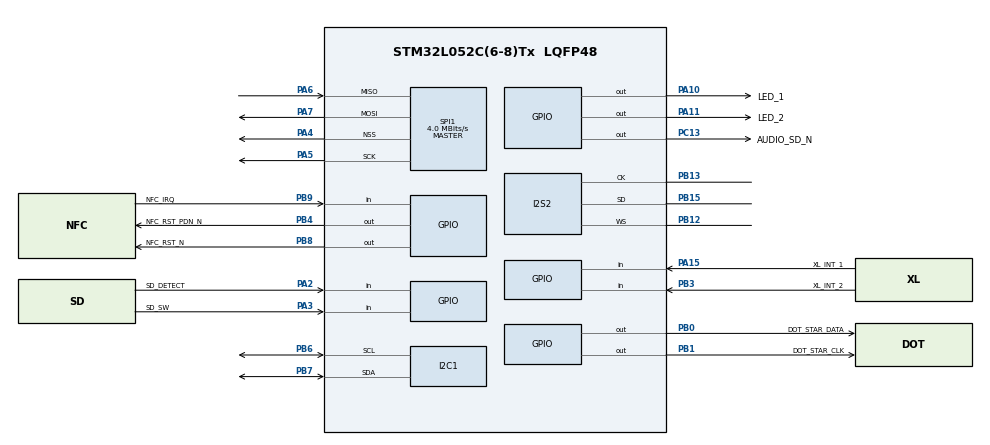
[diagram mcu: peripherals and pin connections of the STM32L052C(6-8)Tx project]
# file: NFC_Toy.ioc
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Dma.Request0=SPI2_TX
Dma.SPI2_TX.0.Direction=DMA_MEMORY_TO_PERIPH
Dma.SPI2_TX.0.Instance=DMA1_Channel5
Dma.SPI2_TX.0.MemDataAlignment=DMA_MDATAALIGN_HALFWORD
Dma.SPI2_TX.0.MemInc=DMA_MINC_ENABLE
Dma.SPI2_TX.0.Mode=DMA_NORMAL
Dma.SPI2_TX.0.PeriphDataAlignment=DMA_PDATAALIGN_HALFWORD
Dma.SPI2_TX.0.PeriphInc=DMA_PINC_DISABLE
Dma.SPI2_TX.0.Priority=DMA_PRIORITY_LOW
FATFS._FS_MINIMIZE=1
I2C1.Timing=0x00303D5B
I2S2.AudioFreq=I2S_AUDIOFREQ_44K
I2S2.ErrorAudioFreq=3.3 %
I2S2.Instance=SPI$Index
I2S2.RealAudioFreq=45.454 KHz
I2S2.VirtualMode=I2S_MODE_MASTER
Mcu.Family=STM32L0
Mcu.Name=STM32L052C(6-8)Tx
Mcu.Package=LQFP48
NVIC.DMA1_Channel4_5_6_7_IRQn=true\:0\:0\:false\:false\:true\:false
PA10.GPIO_Label=LED_1
PA10.Signal=GPIO_Output
PA11.GPIO_Label=LED_2
PA11.Signal=GPIO_Output
PA13.Mode=Serial_Wire
PA13.Signal=SYS_SWDIO
PA14.Mode=Serial_Wire
PA14.Signal=SYS_SWCLK
PA15.GPIO_Label=XL_INT_1
PA15.Signal=GPIO_Input
PA2.GPIO_Label=SD_DETECT
PA2.Signal=GPIO_Input
PA3.GPIO_Label=SD_SW
PA3.Signal=GPIO_Input
PA4.Mode=NSS_Signal_Hard_Output
PA4.Signal=SPI1_NSS
PA5.Mode=Full_Duplex_Master
PA5.Signal=SPI1_SCK
PA6.GPIO_PuPd=GPIO_PULLUP
PA6.Mode=Full_Duplex_Master
PA6.Signal=SPI1_MISO
PA7.Mode=Full_Duplex_Master
PA7.Signal=SPI1_MOSI
PB0.GPIO_Label=DOT_STAR_DATA
PB0.Signal=GPIO_Output
PB1.GPIO_Label=DOT_STAR_CLK
PB1.Signal=GPIO_Output
PB12.Mode=Half_Duplex_Master
PB12.Signal=I2S2_WS
PB13.Mode=Half_Duplex_Master
PB13.Signal=I2S2_CK
PB15.Mode=Half_Duplex_Master
PB15.Signal=I2S2_SD
PB3.GPIO_Label=XL_INT_2
PB3.Signal=GPIO_Input
PB4.GPIO_Label=NFC_RST_PDN_N
PB4.GPIO_ModeDefaultOutputPP=GPIO_MODE_OUTPUT_OD
PB4.PinState=GPIO_PIN_SET
PB4.Signal=GPIO_Output
PB6.GPIO_PuPdOD=GPIO_NOPULL
PB6.Mode=I2C
PB6.Signal=I2C1_SCL
PB7.GPIO_PuPdOD=GPIO_NOPULL
PB7.Mode=I2C
PB7.Signal=I2C1_SDA
PB8.GPIO_Label=NFC_RST_N
PB8.Signal=GPIO_Output
PB9.GPIO_Label=NFC_IRQ
PB9.Signal=GPIO_Input
PC13.GPIO_Label=AUDIO_SD_N
PC13.Signal=GPIO_Output
ProjectManager.HeapSize=0x200
ProjectManager.StackSize=0x400
ProjectManager.TargetToolchain=TrueSTUDIO
RCC.AHBFreq_Value=16000000
RCC.APB1Freq_Value=16000000
RCC.APB1TimFreq_Value=16000000
RCC.APB2Freq_Value=16000000
RCC.APB2TimFreq_Value=16000000
RCC.HCLKFreq_Value=16000000
RCC.HSE_VALUE=8000000
RCC.HSI16_VALUE=16000000
RCC.HSI48_VALUE=48000000
RCC.HSI_VALUE=16000000
RCC.LSE_VALUE=32768
RCC.MSI_VALUE=2097000
RCC.SYSCLKFreq_VALUE=16000000
RCC.SYSCLKSource=RCC_SYSCLKSOURCE_HSI
RCC.VCOOutputFreq_Value=48000000
SPI1.BaudRatePrescaler=SPI_BAUDRATEPRESCALER_4
SPI1.CalculateBaudRate=4.0 MBits/s
SPI1.Direction=SPI_DIRECTION_2LINES
SPI1.Mode=SPI_MODE_MASTER
SPI1.VirtualNSS=VM_NSSHARD
SPI1.VirtualType=VM_MASTER
VP_FATFS_VS_Generic.Mode=User_defined
board=NFC_Toy

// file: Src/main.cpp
/**
  ******************************************************************************
  * @file           : mainc
  * @brief          : Main program body
  ******************************************************************************
  * This notice applies to any and all portions of this file
  * that are not between comment pairs USER CODE BEGIN and
  * USER CODE END Other portions of this file, whether
  * inserted by the user or by software development tools
  * are owned by their respective copyright owners
  *
  * Copyright (c) 2018 STMicroelectronics International NV
  * All rights reserved
  *
  * Redistribution and use in source and binary forms, with or without
  * modification, are permitted, provided that the following conditions are met:
  *
  * 1 Redistribution of source code must retain the above copyright notice,
  *    this list of conditions and the following disclaimer
  * 2 Redistributions in binary form must reproduce the above copyright notice,
  *    this list of conditions and the following disclaimer in the documentation
  *    and/or other materials provided with the distribution
  * 3 Neither the name of STMicroelectronics nor the names of other
  *    contributors to this software may be used to endorse or promote products
  *    derived from this software without specific written permission
  * 4 This software, including modifications and/or derivative works of this
  *    software, must execute solely and exclusively on microcontroller or
  *    microprocessor devices manufactured by or for STMicroelectronics
  * 5 Redistribution and use of this software other than as permitted under
  *    this license is void and will automatically terminate your rights under
  *    this license
  *
  * THIS SOFTWARE IS PROVIDED BY STMICROELECTRONICS AND CONTRIBUTORS "AS IS"
  * AND ANY EXPRESS, IMPLIED OR STATUTORY WARRANTIES, INCLUDING, BUT NOT
  * LIMITED TO, THE IMPLIED WARRANTIES OF MERCHANTABILITY, FITNESS FOR A
  * PARTICULAR PURPOSE AND NON-INFRINGEMENT OF THIRD PARTY INTELLECTUAL PROPERTY
  * RIGHTS ARE DISCLAIMED TO THE FULLEST EXTENT PERMITTED BY LAW IN NO EVENT
  * SHALL STMICROELECTRONICS OR CONTRIBUTORS BE LIABLE FOR ANY DIRECT, INDIRECT,
  * INCIDENTAL, SPECIAL, EXEMPLARY, OR CONSEQUENTIAL DAMAGES (INCLUDING, BUT NOT
  * LIMITED TO, PROCUREMENT OF SUBSTITUTE GOODS OR SERVICES; LOSS OF USE, DATA,
  * OR PROFITS; OR BUSINESS INTERRUPTION) HOWEVER CAUSED AND ON ANY THEORY OF
  * LIABILITY, WHETHER IN CONTRACT, STRICT LIABILITY, OR TORT (INCLUDING
  * NEGLIGENCE OR OTHERWISE) ARISING IN ANY WAY OUT OF THE USE OF THIS SOFTWARE,
  * EVEN IF ADVISED OF THE POSSIBILITY OF SUCH DAMAGE
  *
  ******************************************************************************
  */
#include "main.h"
#include "stm32l0xx_hal.h"
#include "dma.h"
#include "diskio.h"
#include "ff.h"
#include "i2c.h"
#include "i2s.h"
#include "spi.h"
#include "gpio.h"
#include "rng.h"
#include "dotstar.hpp"
#include "ring_effects.hpp"
#include "lis3dh.hpp"
#include "wav_player.h"
#include "pn532.h"
#include "tag_ids.hpp"

/* USER CODE BEGIN PV */
/* Private variables ---------------------------------------------------------*/
FATFS FatFs;

// Loop timer
uint8_t loop_timer_flag = 0;
uint8_t loop_timer = 0;
uint16_t loop_period = 50; // 50ms loop

/* USER CODE END PV */

void SystemClock_Config(void);

/* USER CODE BEGIN PFP */
/* Private function prototypes -----------------------------------------------*/
/* USER CODE END PFP */

int main(void)
{

  /* MCU Configuration----------------------------------------------------------*/

  /* Reset of all peripherals, Initializes the Flash interface and the Systick */
  HAL_Init();

  /* Configure the system clock */
  SystemClock_Config();

  /* Initialize all configured peripherals */
  MX_GPIO_Init();
  MX_DMA_Init();
  MX_I2C1_Init();
  MX_I2S2_Init();
  MX_SPI1_Init();
  MX_RNG_Init();
  /* USER CODE BEGIN 2 */

  // Setup accelerometer
  LIS3DH accel = LIS3DH();
  accel.begin(0x32);
  accel.writeRegister8(LIS3DH_REG_INT1CFG, 0x2A);
  accel.writeRegister8(LIS3DH_REG_INT1THS, 0xBF);
  accel.writeRegister8(LIS3DH_REG_INT1DUR, 0x30);
  accel.writeRegister8(LIS3DH_REG_CTRL3, 0x40);

  // Setup and initialize Dotstars
  DotStar ring = DotStar(16, DOTSTAR_RBG);
  ring.begin(); // Initialize pins for output
  RGB_VALS rgb_off;
  rgb_off.r = 0; rgb_off.g = 0; rgb_off.b = 0;
  ring_set_all_pixels(ring, rgb_off); // Initialize LEDs to off
  uint8_t brightness_all_on = 5;
  uint8_t brightness_ring = 20;

  // Mount SD Card
  FRESULT fr;     /* FatFs return code */
  HAL_GPIO_WritePin(SD_CS_GPIO_Port, SD_CS_Pin, GPIO_PIN_SET);
  fr = f_mount(&FatFs, "", 1);

  // Setup NFC Reader
  HAL_GPIO_WritePin(NFC_RST_PDN_N_GPIO_Port, NFC_RST_PDN_N_Pin, GPIO_PIN_SET);
  PN532 nfc = PN532();
  nfc.begin();
  nfc.SAMConfig();
  bool nfc_found;
  uint8_t uid[] = { 0, 0, 0, 0, 0, 0, 0 };  // Buffer to store the returned UID
  uint8_t uidLength;                        // Length of the UID (4 or 7 bytes depending on ISO14443A card type)
  tag detected_tag;
  tag tag_to_find;
  uint8_t randtagid;
  uint8_t nfc_search_timer = 0;
  uint8_t nfc_search_timeout = 5;

  // State Machine
  enum States { ST_request, ST_search, ST_response };
  States state = ST_request;
  /* USER CODE END 2 */

  /* Infinite loop */
  /* USER CODE BEGIN WHILE */
  // Task Scheduler
  while(1) {

    // State actions
    switch(state) {

      case ST_request:
        // Pick random tag
        randtagid = HAL_RNG_GetRandomNumber(&hrng) % num_tags;
        tag_to_find = tags[randtagid];
        // Turn on LEDs
        ring.setBrightness(brightness_all_on);
        ring_set_all_pixels(ring, tag_to_find.rgb);
        ring.setBrightness(brightness_ring);
        HAL_Delay(500);
        // Audio request
        play_wav(tag_to_find.wav_file_find);
        // Kick-off NFC reader
        nfc.readPassiveTargetID(PN532_MIFARE_ISO14443A, 10);
        nfc_search_timer = 0;
        state = ST_search;
        break;

      case ST_search:
        // Update LED ring on every pass
        ring.decrRing(tag_to_find.rgb);
        // Check if NFC found anything
        nfc_found = nfc.checkPassiveTargetStatus(uid, &uidLength);
        if (nfc_found) {
          detected_tag = find_tag(uid);
          state = ST_response;
        } else {
          // Re-ping NFC every once in a while
          if (nfc_search_timer == nfc_search_timeout) {
            nfc.readPassiveTargetID(PN532_MIFARE_ISO14443A, 10);
            nfc_search_timer = 0;
          } else {
            nfc_search_timer++;
          }
          state = ST_search;
        }
        break;

      case ST_response:
        ring.setBrightness(brightness_all_on);
        ring_set_all_pixels(ring, detected_tag.rgb);
        ring.setBrightness(brightness_ring);
        HAL_Delay(500);
        if (detected_tag.uid[0] == tag_to_find.uid[0]) {
          play_wav(detected_tag.wav_file_found);
        }
        play_wav(detected_tag.wav_file_color);
        ring_set_all_pixels(ring, rgb_off);
        HAL_Delay(500);
        state = ST_request;

      default:
        ST_request;
    }

    loop_timer_flag = 0;
    while (!loop_timer_flag) {
      // wait for timeout
    }

  }
  return 0;
  /* USER CODE END 3 */
}

void SystemClock_Config(void)
{

  RCC_OscInitTypeDef RCC_OscInitStruct;
  RCC_ClkInitTypeDef RCC_ClkInitStruct;
  RCC_PeriphCLKInitTypeDef PeriphClkInit;

    /**Configure the main internal regulator output voltage
    */
  __HAL_PWR_VOLTAGESCALING_CONFIG(PWR_REGULATOR_VOLTAGE_SCALE1);

    /**Initializes the CPU, AHB and APB busses clocks
    */
  RCC_OscInitStruct.OscillatorType = RCC_OSCILLATORTYPE_HSI;
  RCC_OscInitStruct.HSIState = RCC_HSI_ON;
  RCC_OscInitStruct.HSICalibrationValue = 16;
  RCC_OscInitStruct.PLL.PLLState = RCC_PLL_ON;
  RCC_OscInitStruct.PLL.PLLSource = RCC_PLLSOURCE_HSI;
  RCC_OscInitStruct.PLL.PLLMUL = RCC_PLLMUL_4;
  RCC_OscInitStruct.PLL.PLLDIV = RCC_PLLDIV_2;
  if (HAL_RCC_OscConfig(&RCC_OscInitStruct) != HAL_OK)
  {
    _Error_Handler(__FILE__, __LINE__);
  }

    /**Initializes the CPU, AHB and APB busses clocks
    */
  RCC_ClkInitStruct.ClockType = RCC_CLOCKTYPE_HCLK|RCC_CLOCKTYPE_SYSCLK
                              |RCC_CLOCKTYPE_PCLK1|RCC_CLOCKTYPE_PCLK2;
  RCC_ClkInitStruct.SYSCLKSource = RCC_SYSCLKSOURCE_PLLCLK;
  RCC_ClkInitStruct.AHBCLKDivider = RCC_SYSCLK_DIV1;
  RCC_ClkInitStruct.APB1CLKDivider = RCC_HCLK_DIV1;
  RCC_ClkInitStruct.APB2CLKDivider = RCC_HCLK_DIV1;

  if (HAL_RCC_ClockConfig(&RCC_ClkInitStruct, FLASH_LATENCY_1) != HAL_OK)
  {
    _Error_Handler(__FILE__, __LINE__);
  }

  PeriphClkInit.PeriphClockSelection = RCC_PERIPHCLK_I2C1;
  PeriphClkInit.I2c1ClockSelection = RCC_I2C1CLKSOURCE_HSI;
  if (HAL_RCCEx_PeriphCLKConfig(&PeriphClkInit) != HAL_OK)
  {
    _Error_Handler(__FILE__, __LINE__);
  }

    /**Configure the Systick interrupt time
    */
  HAL_SYSTICK_Config(HAL_RCC_GetHCLKFreq()/1000);

    /**Configure the Systick
    */
  HAL_SYSTICK_CLKSourceConfig(SYSTICK_CLKSOURCE_HCLK);

  /* SysTick_IRQn interrupt configuration */
  HAL_NVIC_SetPriority(SysTick_IRQn, 0, 0);
}

/* USER CODE BEGIN 4 */
void HAL_SYSTICK_Callback(void) {
  if (loop_timer == loop_period) {
    loop_timer_flag = 1;
    loop_timer = 0;
  } else {
    loop_timer++;
  }
  return;
}

/* USER CODE END 4 */

void _Error_Handler(char *file, int line)
{
  while(1)
  {
  }
}

/************************ (C) COPYRIGHT STMicroelectronics *****END OF FILE****/
